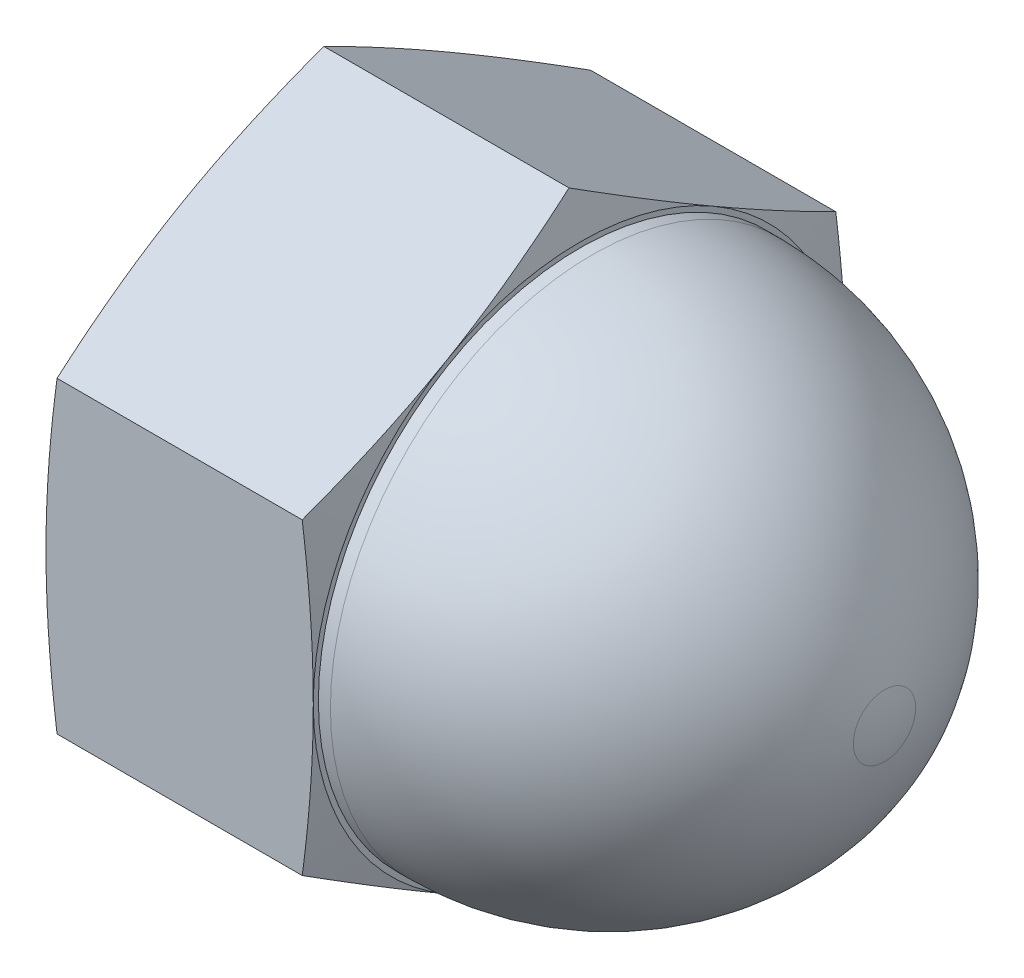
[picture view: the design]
ISO-10303-21;
HEADER;
FILE_DESCRIPTION(('STEP AP214'),'2;1');
FILE_NAME('part.step','',(''),(''),'','','');
FILE_SCHEMA(('AUTOMOTIVE_DESIGN { 1 0 10303 214 1 1 1 1 }'));
ENDSEC;
DATA;
#1=APPLICATION_CONTEXT('core data for automotive mechanical design processes');
#2=APPLICATION_PROTOCOL_DEFINITION('international standard','automotive_design',2000,#1);
#3=PRODUCT_CONTEXT('',#1,'mechanical');
#4=PRODUCT('Part','Part','',(#3));
#5=PRODUCT_RELATED_PRODUCT_CATEGORY('part','',(#4));
#6=PRODUCT_DEFINITION_FORMATION('','',#4);
#7=PRODUCT_DEFINITION_CONTEXT('part definition',#1,'design');
#8=PRODUCT_DEFINITION('design','',#6,#7);
#9=PRODUCT_DEFINITION_SHAPE('','',#8);
#10=(LENGTH_UNIT() NAMED_UNIT(*) SI_UNIT(.MILLI.,.METRE.));
#11=(NAMED_UNIT(*) PLANE_ANGLE_UNIT() SI_UNIT($,.RADIAN.));
#12=(NAMED_UNIT(*) SI_UNIT($,.STERADIAN.) SOLID_ANGLE_UNIT());
#13=UNCERTAINTY_MEASURE_WITH_UNIT(LENGTH_MEASURE(1.E-05),#10,'distance_accuracy_value','');
#14=(GEOMETRIC_REPRESENTATION_CONTEXT(3) GLOBAL_UNCERTAINTY_ASSIGNED_CONTEXT((#13)) GLOBAL_UNIT_ASSIGNED_CONTEXT((#10,
#11,#12)) REPRESENTATION_CONTEXT('',''));
#15=CARTESIAN_POINT('',(0.,0.,0.));
#16=DIRECTION('',(0.,0.,1.));
#17=DIRECTION('',(1.,0.,0.));
#18=AXIS2_PLACEMENT_3D('',#15,#16,#17);
#19=CARTESIAN_POINT('',(18.288,21.0805017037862,0.));
#20=DIRECTION('',(-1.,0.,0.));
#21=DIRECTION('',(0.,0.,1.));
#22=AXIS2_PLACEMENT_3D('',#19,#20,#21);
#23=PLANE('',#22);
#24=CARTESIAN_POINT('',(18.288,0.,0.));
#25=DIRECTION('',(-1.,0.,0.));
#26=DIRECTION('',(0.,0.,1.));
#27=AXIS2_PLACEMENT_3D('',#24,#25,#26);
#28=CIRCLE('',#27,17.907);
#29=CARTESIAN_POINT('',(18.288,0.,17.907));
#30=VERTEX_POINT('',#29);
#31=EDGE_CURVE('E308',#30,#30,#28,.F.);
#32=ORIENTED_EDGE('',*,*,#31,.F.);
#33=EDGE_LOOP('',(#32));
#34=FACE_BOUND('',#33,.T.);
#35=CARTESIAN_POINT('',(18.288,0.,0.));
#36=DIRECTION('',(-1.,0.,0.));
#37=DIRECTION('',(0.,0.,1.));
#38=AXIS2_PLACEMENT_3D('',#35,#36,#37);
#39=CIRCLE('',#38,18.25625);
#40=CARTESIAN_POINT('',(18.288,0.,18.25625));
#41=VERTEX_POINT('',#40);
#42=CARTESIAN_POINT('',(18.288,15.8103762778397,9.12812499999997));
#43=VERTEX_POINT('',#42);
#44=EDGE_CURVE('E279',#41,#43,#39,.T.);
#45=ORIENTED_EDGE('',*,*,#44,.F.);
#46=CARTESIAN_POINT('',(18.288,0.,0.));
#47=DIRECTION('',(-1.,0.,0.));
#48=DIRECTION('',(0.,0.,1.));
#49=AXIS2_PLACEMENT_3D('',#46,#47,#48);
#50=CIRCLE('',#49,18.25625);
#51=CARTESIAN_POINT('',(18.288,-15.8103762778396,9.12812500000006));
#52=VERTEX_POINT('',#51);
#53=EDGE_CURVE('E44',#52,#41,#50,.T.);
#54=ORIENTED_EDGE('',*,*,#53,.F.);
#55=CARTESIAN_POINT('',(18.288,-15.8103762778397,-9.12812499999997));
#56=VERTEX_POINT('',#55);
#57=EDGE_CURVE('E302',#56,#52,#50,.T.);
#58=ORIENTED_EDGE('',*,*,#57,.F.);
#59=CARTESIAN_POINT('',(18.288,0.,-18.25625));
#60=VERTEX_POINT('',#59);
#61=EDGE_CURVE('E360',#60,#56,#50,.T.);
#62=ORIENTED_EDGE('',*,*,#61,.F.);
#63=CARTESIAN_POINT('',(18.288,15.8103762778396,-9.12812500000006));
#64=VERTEX_POINT('',#63);
#65=EDGE_CURVE('E42',#64,#60,#50,.T.);
#66=ORIENTED_EDGE('',*,*,#65,.F.);
#67=EDGE_CURVE('E11',#43,#64,#50,.T.);
#68=ORIENTED_EDGE('',*,*,#67,.F.);
#69=EDGE_LOOP('',(#45,#54,#58,#62,#66,#68));
#70=FACE_BOUND('',#69,.T.);
#71=ADVANCED_FACE('F32',(#34,#70),#23,.F.);
#72=CARTESIAN_POINT('',(0.,0.,0.));
#73=DIRECTION('',(-1.,0.,0.));
#74=DIRECTION('',(0.,0.,1.));
#75=AXIS2_PLACEMENT_3D('',#72,#73,#74);
#76=CYLINDRICAL_SURFACE('',#75,17.907);
#77=CARTESIAN_POINT('',(19.1115044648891,0.,0.));
#78=DIRECTION('',(-1.,0.,0.));
#79=DIRECTION('',(0.,0.,1.));
#80=AXIS2_PLACEMENT_3D('',#77,#78,#79);
#81=CIRCLE('',#80,17.907);
#82=CARTESIAN_POINT('',(19.1115044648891,0.,17.907));
#83=VERTEX_POINT('',#82);
#84=EDGE_CURVE('E326',#83,#83,#81,.T.);
#85=ORIENTED_EDGE('',*,*,#84,.T.);
#86=EDGE_LOOP('',(#85));
#87=FACE_BOUND('',#86,.T.);
#88=ORIENTED_EDGE('',*,*,#31,.T.);
#89=EDGE_LOOP('',(#88));
#90=FACE_BOUND('',#89,.T.);
#91=ADVANCED_FACE('F145',(#87,#90),#76,.T.);
#92=CARTESIAN_POINT('',(19.1115044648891,0.,0.));
#93=DIRECTION('',(-1.,0.,0.));
#94=DIRECTION('',(0.,0.,1.));
#95=AXIS2_PLACEMENT_3D('',#92,#93,#94);
#96=DEGENERATE_TOROIDAL_SURFACE('',#95,2.66700000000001,20.574,.F.);
#97=ORIENTED_EDGE('',*,*,#84,.F.);
#98=EDGE_LOOP('',(#97));
#99=FACE_BOUND('',#98,.T.);
#100=CARTESIAN_POINT('',(39.1175964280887,0.,0.));
#101=DIRECTION('',(-1.,0.,0.));
#102=DIRECTION('',(0.,0.,1.));
#103=AXIS2_PLACEMENT_3D('',#100,#101,#102);
#104=CIRCLE('',#103,2.13360000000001);
#105=CARTESIAN_POINT('',(39.1175964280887,0.,2.13360000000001));
#106=VERTEX_POINT('',#105);
#107=EDGE_CURVE('E330',#106,#106,#104,.T.);
#108=ORIENTED_EDGE('',*,*,#107,.T.);
#109=EDGE_LOOP('',(#108));
#110=FACE_BOUND('',#109,.T.);
#111=ADVANCED_FACE('F151',(#99,#110),#96,.F.);
#112=CARTESIAN_POINT('',(30.226,0.,0.));
#113=DIRECTION('',(-1.,0.,0.));
#114=DIRECTION('',(0.,1.,0.));
#115=AXIS2_PLACEMENT_3D('',#112,#113,#114);
#116=SPHERICAL_SURFACE('',#115,9.144);
#117=ORIENTED_EDGE('',*,*,#107,.F.);
#118=EDGE_LOOP('',(#117));
#119=FACE_BOUND('',#118,.T.);
#120=ADVANCED_FACE('F210',(#119),#116,.T.);
#121=CARTESIAN_POINT('',(16.3329343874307,0.,0.));
#122=DIRECTION('',(-1.,0.,0.));
#123=DIRECTION('',(0.,0.,1.));
#124=AXIS2_PLACEMENT_3D('',#121,#122,#123);
#125=CONICAL_SURFACE('',#124,25.5539793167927,1.30904233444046);
#126=CARTESIAN_POINT('',(14.23452834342,-27.9532654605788,18.25625));
#127=CARTESIAN_POINT('',(14.3275034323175,-27.5387474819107,18.25625));
#128=CARTESIAN_POINT('',(14.4198935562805,-27.1240983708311,18.25625));
#129=CARTESIAN_POINT('',(14.6033753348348,-26.2945115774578,18.25625));
#130=CARTESIAN_POINT('',(14.6944669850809,-25.8795738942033,18.25625));
#131=CARTESIAN_POINT('',(14.9656076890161,-24.6342596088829,18.25625));
#132=CARTESIAN_POINT('',(15.1435150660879,-23.8034148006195,18.25625));
#133=CARTESIAN_POINT('',(15.4925052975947,-22.1394500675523,18.25625));
#134=CARTESIAN_POINT('',(15.6635813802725,-21.306328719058,18.25625));
#135=CARTESIAN_POINT('',(15.9970880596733,-19.6383578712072,18.25625));
#136=CARTESIAN_POINT('',(16.1595187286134,-18.8035083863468,18.25625));
#137=CARTESIAN_POINT('',(16.4724176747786,-17.1384385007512,18.25625));
#138=CARTESIAN_POINT('',(16.622970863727,-16.3082341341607,18.25625));
#139=CARTESIAN_POINT('',(16.9110143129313,-14.6455443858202,18.25625));
#140=CARTESIAN_POINT('',(17.0485045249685,-13.8130589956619,18.25625));
#141=CARTESIAN_POINT('',(17.3073349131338,-12.1456689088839,18.25625));
#142=CARTESIAN_POINT('',(17.428677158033,-11.3107645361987,18.25625));
#143=CARTESIAN_POINT('',(17.6516508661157,-9.63829765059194,18.25625));
#144=CARTESIAN_POINT('',(17.7532823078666,-8.80073513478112,18.25625));
#145=CARTESIAN_POINT('',(17.9339717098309,-7.11347642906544,18.25625));
#146=CARTESIAN_POINT('',(18.0127589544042,-6.26375081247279,18.25625));
#147=CARTESIAN_POINT('',(18.1423348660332,-4.56214896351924,18.25625));
#148=CARTESIAN_POINT('',(18.1931241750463,-3.71027278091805,18.25625));
#149=CARTESIAN_POINT('',(18.2637429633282,-2.00560726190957,18.25625));
#150=CARTESIAN_POINT('',(18.2835867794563,-1.15281853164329,18.25625));
#151=CARTESIAN_POINT('',(18.2910929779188,0.552902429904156,18.25625));
#152=CARTESIAN_POINT('',(18.278755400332,1.40583466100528,18.25625));
#153=CARTESIAN_POINT('',(18.2225918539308,3.11375554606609,18.25625));
#154=CARTESIAN_POINT('',(18.1786511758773,3.96874035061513,18.25625));
#155=CARTESIAN_POINT('',(18.0617958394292,5.67670937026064,18.25625));
#156=CARTESIAN_POINT('',(17.9888805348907,6.52969354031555,18.25625));
#157=CARTESIAN_POINT('',(17.8177764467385,8.23365261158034,18.25625));
#158=CARTESIAN_POINT('',(17.7195710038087,9.08462581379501,18.25625));
#159=CARTESIAN_POINT('',(17.5019945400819,10.7838317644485,18.25625));
#160=CARTESIAN_POINT('',(17.3826234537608,11.6320645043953,18.25625));
#161=CARTESIAN_POINT('',(17.134092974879,13.2760153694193,18.25625));
#162=CARTESIAN_POINT('',(17.0059238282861,14.0718847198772,18.25625));
#163=CARTESIAN_POINT('',(16.7370148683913,15.6615074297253,18.25625));
#164=CARTESIAN_POINT('',(16.5962747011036,16.4552607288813,18.25625));
#165=CARTESIAN_POINT('',(16.304536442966,18.0409557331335,18.25625));
#166=CARTESIAN_POINT('',(16.1535372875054,18.8328972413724,18.25625));
#167=CARTESIAN_POINT('',(15.8431874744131,20.415128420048,18.25625));
#168=CARTESIAN_POINT('',(15.6838368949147,21.2054181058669,18.25625));
#169=CARTESIAN_POINT('',(15.358261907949,22.7847826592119,18.25625));
#170=CARTESIAN_POINT('',(15.1920357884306,23.5738571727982,18.25625));
#171=CARTESIAN_POINT('',(14.85396082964,25.1507994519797,18.25625));
#172=CARTESIAN_POINT('',(14.6821119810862,25.9386672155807,18.25625));
#173=CARTESIAN_POINT('',(14.3337740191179,27.5133202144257,18.25625));
#174=CARTESIAN_POINT('',(14.1572852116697,28.3001055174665,18.25625));
#175=CARTESIAN_POINT('',(13.8004259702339,29.8727961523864,18.25625));
#176=CARTESIAN_POINT('',(13.6200555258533,30.6587014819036,18.25625));
#177=CARTESIAN_POINT('',(13.0776878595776,32.9997553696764,18.25625));
#178=CARTESIAN_POINT('',(12.7109621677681,34.5538083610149,18.25625));
#179=CARTESIAN_POINT('',(11.9683855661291,37.6597542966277,18.25625));
#180=CARTESIAN_POINT('',(11.5925344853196,39.2116471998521,18.25625));
#181=CARTESIAN_POINT('',(10.8345439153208,42.3118217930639,18.25625));
#182=CARTESIAN_POINT('',(10.4524129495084,43.8601055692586,18.25625));
#183=CARTESIAN_POINT('',(9.87538294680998,46.1815493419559,18.25625));
#184=CARTESIAN_POINT('',(9.68240387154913,46.9551876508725,18.25625));
#185=CARTESIAN_POINT('',(9.29531367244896,48.5021801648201,18.25625));
#186=CARTESIAN_POINT('',(9.10120254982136,49.2755343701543,18.25625));
#187=CARTESIAN_POINT('',(8.90659910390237,50.0487647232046,18.25625));
#188=B_SPLINE_CURVE_WITH_KNOTS('',3,(#126,#127,#128,#129,#130,#131,#132,#133,#134,#135,#136,
#137,#138,#139,#140,#141,#142,#143,#144,#145,#146,#147,#148,#149,#150,#151,#152,#153,#154,#155,
#156,#157,#158,#159,#160,#161,#162,#163,#164,#165,#166,#167,#168,#169,#170,#171,#172,#173,#174,
#175,#176,#177,#178,#179,#180,#181,#182,#183,#184,#185,#186,#187),.UNSPECIFIED.,.F.,.F.,(4,2,2,
2,2,2,2,2,2,2,2,2,2,2,2,2,2,2,2,2,2,2,2,2,2,2,2,2,2,2,4),(0.,1.27445034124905,2.54890494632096,
5.0979157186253,7.64939354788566,10.2008500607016,12.7320016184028,15.2631625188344,
17.7939988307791,20.3248378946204,22.8845458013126,25.4441950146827,28.0026580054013,
30.5611178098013,33.1289111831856,35.6967618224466,38.2663083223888,40.8358627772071,
43.2541145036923,45.6724343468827,48.0910055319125,50.509554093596,52.928708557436,
55.3478670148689,57.7668663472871,60.1858721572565,64.976038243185,69.7662941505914,
74.5505121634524,76.9425429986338,79.3345712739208),.UNSPECIFIED.);
#189=CARTESIAN_POINT('',(17.5313814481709,-10.5402508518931,18.25625));
#190=VERTEX_POINT('',#189);
#191=EDGE_CURVE('E233',#41,#190,#188,.F.);
#192=ORIENTED_EDGE('',*,*,#191,.T.);
#193=CARTESIAN_POINT('',(17.5313505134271,-10.5401353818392,18.25645));
#194=CARTESIAN_POINT('',(17.5899853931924,-10.7590105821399,17.8773470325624));
#195=CARTESIAN_POINT('',(17.6459340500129,-10.978065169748,17.4979333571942));
#196=CARTESIAN_POINT('',(17.7519028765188,-11.4165429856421,16.7384675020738));
#197=CARTESIAN_POINT('',(17.8019227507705,-11.6359662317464,16.3584152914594));
#198=CARTESIAN_POINT('',(17.9422800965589,-12.2949280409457,15.2170599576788));
#199=CARTESIAN_POINT('',(18.0228725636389,-12.7350021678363,14.4548292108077));
#200=CARTESIAN_POINT('',(18.1534715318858,-13.6140162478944,12.9323321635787));
#201=CARTESIAN_POINT('',(18.2036336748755,-14.0529503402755,12.1720760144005));
#202=CARTESIAN_POINT('',(18.2708947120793,-14.9313817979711,10.650588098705));
#203=CARTESIAN_POINT('',(18.288,-15.3708790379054,9.88935654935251));
#204=CARTESIAN_POINT('',(18.288,-16.249873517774,8.36689345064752));
#205=CARTESIAN_POINT('',(18.2708947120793,-16.6893707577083,7.60566190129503));
#206=CARTESIAN_POINT('',(18.2036336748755,-17.5678022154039,6.08417398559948));
#207=CARTESIAN_POINT('',(18.1534715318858,-18.0067363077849,5.32391783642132));
#208=CARTESIAN_POINT('',(18.0228725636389,-18.885750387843,3.80142078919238));
#209=CARTESIAN_POINT('',(17.9422800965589,-19.3258245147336,3.03919004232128));
#210=CARTESIAN_POINT('',(17.8019227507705,-19.9847863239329,1.89783470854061));
#211=CARTESIAN_POINT('',(17.7519028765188,-20.2042095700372,1.51778249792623));
#212=CARTESIAN_POINT('',(17.6459340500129,-20.6426873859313,0.758316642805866));
#213=CARTESIAN_POINT('',(17.5899853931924,-20.8617419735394,0.378902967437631));
#214=CARTESIAN_POINT('',(17.5313505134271,-21.0806171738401,-0.000199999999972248));
#215=B_SPLINE_CURVE_WITH_KNOTS('',3,(#193,#194,#195,#196,#197,#198,#199,#200,#201,#202,#203,
#204,#205,#206,#207,#208,#209,#210,#211,#212,#213,#214),.UNSPECIFIED.,.F.,.F.,(4,2,2,2,2,2,2,2,
2,2,4),(0.,1.32496515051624,2.64999629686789,5.30100599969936,7.93833969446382,10.5751632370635,
13.2119867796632,15.8493204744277,18.5003301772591,19.8253613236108,21.150326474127),.UNSPECIFIED.);
#216=EDGE_CURVE('E231',#190,#52,#215,.T.);
#217=ORIENTED_EDGE('',*,*,#216,.T.);
#218=ORIENTED_EDGE('',*,*,#53,.T.);
#219=EDGE_LOOP('',(#192,#217,#218));
#220=FACE_BOUND('',#219,.T.);
#221=ADVANCED_FACE('F356',(#220),#125,.T.);
#222=CARTESIAN_POINT('',(17.5313814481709,-21.0805017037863,0.));
#223=VERTEX_POINT('',#222);
#224=EDGE_CURVE('E226',#52,#223,#215,.T.);
#225=ORIENTED_EDGE('',*,*,#224,.T.);
#226=CARTESIAN_POINT('',(17.5313505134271,-21.0806171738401,0.000200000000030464));
#227=CARTESIAN_POINT('',(17.5899853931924,-20.8617419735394,-0.378902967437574));
#228=CARTESIAN_POINT('',(17.6459340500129,-20.6426873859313,-0.758316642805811));
#229=CARTESIAN_POINT('',(17.7519028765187,-20.2042095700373,-1.51778249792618));
#230=CARTESIAN_POINT('',(17.8019227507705,-19.9847863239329,-1.89783470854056));
#231=CARTESIAN_POINT('',(17.9422800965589,-19.3258245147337,-3.03919004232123));
#232=CARTESIAN_POINT('',(18.0228725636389,-18.885750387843,-3.80142078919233));
#233=CARTESIAN_POINT('',(18.1534715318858,-18.006736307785,-5.32391783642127));
#234=CARTESIAN_POINT('',(18.2036336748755,-17.5678022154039,-6.08417398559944));
#235=CARTESIAN_POINT('',(18.2708947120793,-16.6893707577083,-7.60566190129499));
#236=CARTESIAN_POINT('',(18.288,-16.249873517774,-8.36689345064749));
#237=CARTESIAN_POINT('',(18.288,-15.3708790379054,-9.88935654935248));
#238=CARTESIAN_POINT('',(18.2708947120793,-14.9313817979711,-10.650588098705));
#239=CARTESIAN_POINT('',(18.2036336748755,-14.0529503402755,-12.1720760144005));
#240=CARTESIAN_POINT('',(18.1534715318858,-13.6140162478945,-12.9323321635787));
#241=CARTESIAN_POINT('',(18.0228725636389,-12.7350021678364,-14.4548292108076));
#242=CARTESIAN_POINT('',(17.9422800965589,-12.2949280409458,-15.2170599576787));
#243=CARTESIAN_POINT('',(17.8019227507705,-11.6359662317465,-16.3584152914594));
#244=CARTESIAN_POINT('',(17.7519028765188,-11.4165429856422,-16.7384675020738));
#245=CARTESIAN_POINT('',(17.6459340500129,-10.9780651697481,-17.4979333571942));
#246=CARTESIAN_POINT('',(17.5899853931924,-10.75901058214,-17.8773470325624));
#247=CARTESIAN_POINT('',(17.5313505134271,-10.5401353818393,-18.25645));
#248=B_SPLINE_CURVE_WITH_KNOTS('',3,(#226,#227,#228,#229,#230,#231,#232,#233,#234,#235,#236,
#237,#238,#239,#240,#241,#242,#243,#244,#245,#246,#247),.UNSPECIFIED.,.F.,.F.,(4,2,2,2,2,2,2,2,
2,2,4),(0.,1.32496515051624,2.64999629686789,5.30100599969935,7.93833969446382,10.5751632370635,
13.2119867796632,15.8493204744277,18.5003301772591,19.8253613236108,21.150326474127),.UNSPECIFIED.);
#249=EDGE_CURVE('E232',#223,#56,#248,.T.);
#250=ORIENTED_EDGE('',*,*,#249,.T.);
#251=ORIENTED_EDGE('',*,*,#57,.T.);
#252=EDGE_LOOP('',(#225,#250,#251));
#253=FACE_BOUND('',#252,.T.);
#254=ADVANCED_FACE('F362',(#253),#125,.T.);
#255=CARTESIAN_POINT('',(17.5313814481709,-10.5402508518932,-18.25625));
#256=VERTEX_POINT('',#255);
#257=EDGE_CURVE('E221',#56,#256,#248,.T.);
#258=ORIENTED_EDGE('',*,*,#257,.T.);
#259=CARTESIAN_POINT('',(14.23452834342,-27.953265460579,-18.25625));
#260=CARTESIAN_POINT('',(14.3275034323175,-27.5387474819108,-18.25625));
#261=CARTESIAN_POINT('',(14.4198935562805,-27.1240983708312,-18.25625));
#262=CARTESIAN_POINT('',(14.6033753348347,-26.2945115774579,-18.25625));
#263=CARTESIAN_POINT('',(14.6944669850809,-25.8795738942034,-18.25625));
#264=CARTESIAN_POINT('',(14.965607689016,-24.634259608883,-18.25625));
#265=CARTESIAN_POINT('',(15.1435150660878,-23.8034148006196,-18.25625));
#266=CARTESIAN_POINT('',(15.4925052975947,-22.1394500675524,-18.25625));
#267=CARTESIAN_POINT('',(15.6635813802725,-21.3063287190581,-18.25625));
#268=CARTESIAN_POINT('',(15.9970880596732,-19.6383578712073,-18.25625));
#269=CARTESIAN_POINT('',(16.1595187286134,-18.8035083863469,-18.25625));
#270=CARTESIAN_POINT('',(16.4724176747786,-17.1384385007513,-18.25625));
#271=CARTESIAN_POINT('',(16.622970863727,-16.3082341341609,-18.25625));
#272=CARTESIAN_POINT('',(16.9110143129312,-14.6455443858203,-18.25625));
#273=CARTESIAN_POINT('',(17.0485045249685,-13.813058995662,-18.25625));
#274=CARTESIAN_POINT('',(17.3073349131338,-12.145668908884,-18.25625));
#275=CARTESIAN_POINT('',(17.428677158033,-11.3107645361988,-18.25625));
#276=CARTESIAN_POINT('',(17.6516508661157,-9.63829765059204,-18.25625));
#277=CARTESIAN_POINT('',(17.7532823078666,-8.80073513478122,-18.25625));
#278=CARTESIAN_POINT('',(17.9339717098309,-7.11347642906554,-18.25625));
#279=CARTESIAN_POINT('',(18.0127589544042,-6.26375081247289,-18.25625));
#280=CARTESIAN_POINT('',(18.1423348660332,-4.56214896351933,-18.25625));
#281=CARTESIAN_POINT('',(18.1931241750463,-3.71027278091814,-18.25625));
#282=CARTESIAN_POINT('',(18.2637429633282,-2.00560726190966,-18.25625));
#283=CARTESIAN_POINT('',(18.2835867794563,-1.15281853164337,-18.25625));
#284=CARTESIAN_POINT('',(18.2910929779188,0.55290242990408,-18.25625));
#285=CARTESIAN_POINT('',(18.278755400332,1.40583466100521,-18.25625));
#286=CARTESIAN_POINT('',(18.2225918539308,3.11375554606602,-18.25625));
#287=CARTESIAN_POINT('',(18.1786511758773,3.96874035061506,-18.25625));
#288=CARTESIAN_POINT('',(18.0617958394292,5.67670937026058,-18.25625));
#289=CARTESIAN_POINT('',(17.9888805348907,6.52969354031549,-18.25625));
#290=CARTESIAN_POINT('',(17.8177764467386,8.23365261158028,-18.25625));
#291=CARTESIAN_POINT('',(17.7195710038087,9.08462581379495,-18.25625));
#292=CARTESIAN_POINT('',(17.5019945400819,10.7838317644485,-18.25625));
#293=CARTESIAN_POINT('',(17.3826234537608,11.6320645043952,-18.25625));
#294=CARTESIAN_POINT('',(17.134092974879,13.2760153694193,-18.25625));
#295=CARTESIAN_POINT('',(17.0059238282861,14.0718847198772,-18.25625));
#296=CARTESIAN_POINT('',(16.7370148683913,15.6615074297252,-18.25625));
#297=CARTESIAN_POINT('',(16.5962747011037,16.4552607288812,-18.25625));
#298=CARTESIAN_POINT('',(16.304536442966,18.0409557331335,-18.25625));
#299=CARTESIAN_POINT('',(16.1535372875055,18.8328972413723,-18.25625));
#300=CARTESIAN_POINT('',(15.8431874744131,20.415128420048,-18.25625));
#301=CARTESIAN_POINT('',(15.6838368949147,21.2054181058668,-18.25625));
#302=CARTESIAN_POINT('',(15.358261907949,22.7847826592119,-18.25625));
#303=CARTESIAN_POINT('',(15.1920357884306,23.5738571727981,-18.25625));
#304=CARTESIAN_POINT('',(14.85396082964,25.1507994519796,-18.25625));
#305=CARTESIAN_POINT('',(14.6821119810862,25.9386672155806,-18.25625));
#306=CARTESIAN_POINT('',(14.3337740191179,27.5133202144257,-18.25625));
#307=CARTESIAN_POINT('',(14.1572852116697,28.3001055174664,-18.25625));
#308=CARTESIAN_POINT('',(13.8004259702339,29.8727961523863,-18.25625));
#309=CARTESIAN_POINT('',(13.6200555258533,30.6587014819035,-18.25625));
#310=CARTESIAN_POINT('',(13.0776878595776,32.9997553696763,-18.25625));
#311=CARTESIAN_POINT('',(12.7109621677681,34.5538083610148,-18.25625));
#312=CARTESIAN_POINT('',(11.9683855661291,37.6597542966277,-18.25625));
#313=CARTESIAN_POINT('',(11.5925344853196,39.2116471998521,-18.25625));
#314=CARTESIAN_POINT('',(10.8345439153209,42.3118217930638,-18.25625));
#315=CARTESIAN_POINT('',(10.4524129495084,43.8601055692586,-18.25625));
#316=CARTESIAN_POINT('',(9.87538294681,46.1815493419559,-18.25625));
#317=CARTESIAN_POINT('',(9.68240387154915,46.9551876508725,-18.25625));
#318=CARTESIAN_POINT('',(9.29531367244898,48.5021801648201,-18.25625));
#319=CARTESIAN_POINT('',(9.10120254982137,49.2755343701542,-18.25625));
#320=CARTESIAN_POINT('',(8.90659910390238,50.0487647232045,-18.25625));
#321=B_SPLINE_CURVE_WITH_KNOTS('',3,(#259,#260,#261,#262,#263,#264,#265,#266,#267,#268,#269,
#270,#271,#272,#273,#274,#275,#276,#277,#278,#279,#280,#281,#282,#283,#284,#285,#286,#287,#288,
#289,#290,#291,#292,#293,#294,#295,#296,#297,#298,#299,#300,#301,#302,#303,#304,#305,#306,#307,
#308,#309,#310,#311,#312,#313,#314,#315,#316,#317,#318,#319,#320),.UNSPECIFIED.,.F.,.F.,(4,2,2,
2,2,2,2,2,2,2,2,2,2,2,2,2,2,2,2,2,2,2,2,2,2,2,2,2,2,2,4),(0.,1.27445034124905,2.54890494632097,
5.09791571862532,7.64939354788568,10.2008500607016,12.7320016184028,15.2631625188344,
17.7939988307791,20.3248378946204,22.8845458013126,25.4441950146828,28.0026580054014,
30.5611178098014,33.1289111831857,35.6967618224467,38.2663083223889,40.8358627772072,
43.2541145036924,45.6724343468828,48.0910055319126,50.5095540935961,52.9287085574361,
55.347867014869,57.7668663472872,60.1858721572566,64.9760382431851,69.7662941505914,
74.5505121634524,76.9425429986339,79.3345712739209),.UNSPECIFIED.);
#322=EDGE_CURVE('E58',#60,#256,#321,.F.);
#323=ORIENTED_EDGE('',*,*,#322,.F.);
#324=ORIENTED_EDGE('',*,*,#61,.T.);
#325=EDGE_LOOP('',(#258,#323,#324));
#326=FACE_BOUND('',#325,.T.);
#327=ADVANCED_FACE('F206',(#326),#125,.T.);
#328=CARTESIAN_POINT('',(17.5313505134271,10.5401353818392,-18.25645));
#329=CARTESIAN_POINT('',(17.5899853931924,10.7590105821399,-17.8773470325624));
#330=CARTESIAN_POINT('',(17.6459340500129,10.978065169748,-17.4979333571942));
#331=CARTESIAN_POINT('',(17.7519028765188,11.4165429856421,-16.7384675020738));
#332=CARTESIAN_POINT('',(17.8019227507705,11.6359662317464,-16.3584152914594));
#333=CARTESIAN_POINT('',(17.9422800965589,12.2949280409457,-15.2170599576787));
#334=CARTESIAN_POINT('',(18.0228725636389,12.7350021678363,-14.4548292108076));
#335=CARTESIAN_POINT('',(18.1534715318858,13.6140162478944,-12.9323321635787));
#336=CARTESIAN_POINT('',(18.2036336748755,14.0529503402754,-12.1720760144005));
#337=CARTESIAN_POINT('',(18.2708947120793,14.931381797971,-10.650588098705));
#338=CARTESIAN_POINT('',(18.288,15.3708790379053,-9.88935654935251));
#339=CARTESIAN_POINT('',(18.288,16.2498735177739,-8.36689345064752));
#340=CARTESIAN_POINT('',(18.2708947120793,16.6893707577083,-7.60566190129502));
#341=CARTESIAN_POINT('',(18.2036336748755,17.5678022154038,-6.08417398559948));
#342=CARTESIAN_POINT('',(18.1534715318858,18.0067363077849,-5.32391783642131));
#343=CARTESIAN_POINT('',(18.0228725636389,18.885750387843,-3.80142078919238));
#344=CARTESIAN_POINT('',(17.9422800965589,19.3258245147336,-3.03919004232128));
#345=CARTESIAN_POINT('',(17.8019227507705,19.9847863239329,-1.89783470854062));
#346=CARTESIAN_POINT('',(17.7519028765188,20.2042095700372,-1.51778249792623));
#347=CARTESIAN_POINT('',(17.6459340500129,20.6426873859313,-0.758316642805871));
#348=CARTESIAN_POINT('',(17.5899853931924,20.8617419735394,-0.378902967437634));
#349=CARTESIAN_POINT('',(17.5313505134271,21.0806171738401,0.000199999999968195));
#350=B_SPLINE_CURVE_WITH_KNOTS('',3,(#328,#329,#330,#331,#332,#333,#334,#335,#336,#337,#338,
#339,#340,#341,#342,#343,#344,#345,#346,#347,#348,#349),.UNSPECIFIED.,.F.,.F.,(4,2,2,2,2,2,2,2,
2,2,4),(0.,1.32496515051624,2.6499962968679,5.30100599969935,7.93833969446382,10.5751632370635,
13.2119867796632,15.8493204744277,18.5003301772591,19.8253613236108,21.150326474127),.UNSPECIFIED.);
#351=CARTESIAN_POINT('',(17.5313814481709,10.5402508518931,-18.25625));
#352=VERTEX_POINT('',#351);
#353=EDGE_CURVE('E189',#352,#64,#350,.T.);
#354=ORIENTED_EDGE('',*,*,#353,.T.);
#355=ORIENTED_EDGE('',*,*,#65,.T.);
#356=EDGE_CURVE('E196',#352,#60,#321,.F.);
#357=ORIENTED_EDGE('',*,*,#356,.F.);
#358=EDGE_LOOP('',(#354,#355,#357));
#359=FACE_BOUND('',#358,.T.);
#360=ADVANCED_FACE('F201',(#359),#125,.T.);
#361=CARTESIAN_POINT('',(17.5313505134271,21.0806171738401,-0.000200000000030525));
#362=CARTESIAN_POINT('',(17.5899853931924,20.8617419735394,0.378902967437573));
#363=CARTESIAN_POINT('',(17.6459340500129,20.6426873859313,0.75831664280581));
#364=CARTESIAN_POINT('',(17.7519028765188,20.2042095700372,1.51778249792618));
#365=CARTESIAN_POINT('',(17.8019227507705,19.9847863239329,1.89783470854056));
#366=CARTESIAN_POINT('',(17.9422800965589,19.3258245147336,3.03919004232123));
#367=CARTESIAN_POINT('',(18.0228725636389,18.885750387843,3.80142078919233));
#368=CARTESIAN_POINT('',(18.1534715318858,18.006736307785,5.32391783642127));
#369=CARTESIAN_POINT('',(18.2036336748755,17.5678022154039,6.08417398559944));
#370=CARTESIAN_POINT('',(18.2708947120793,16.6893707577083,7.60566190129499));
#371=CARTESIAN_POINT('',(18.288,16.249873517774,8.36689345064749));
#372=CARTESIAN_POINT('',(18.288,15.3708790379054,9.88935654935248));
#373=CARTESIAN_POINT('',(18.2708947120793,14.9313817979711,10.650588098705));
#374=CARTESIAN_POINT('',(18.2036336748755,14.0529503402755,12.1720760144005));
#375=CARTESIAN_POINT('',(18.1534715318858,13.6140162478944,12.9323321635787));
#376=CARTESIAN_POINT('',(18.0228725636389,12.7350021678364,14.4548292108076));
#377=CARTESIAN_POINT('',(17.9422800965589,12.2949280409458,15.2170599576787));
#378=CARTESIAN_POINT('',(17.8019227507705,11.6359662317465,16.3584152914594));
#379=CARTESIAN_POINT('',(17.7519028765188,11.4165429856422,16.7384675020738));
#380=CARTESIAN_POINT('',(17.6459340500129,10.9780651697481,17.4979333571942));
#381=CARTESIAN_POINT('',(17.5899853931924,10.75901058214,17.8773470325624));
#382=CARTESIAN_POINT('',(17.5313505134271,10.5401353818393,18.25645));
#383=B_SPLINE_CURVE_WITH_KNOTS('',3,(#361,#362,#363,#364,#365,#366,#367,#368,#369,#370,#371,
#372,#373,#374,#375,#376,#377,#378,#379,#380,#381,#382),.UNSPECIFIED.,.F.,.F.,(4,2,2,2,2,2,2,2,
2,2,4),(0.,1.32496515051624,2.6499962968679,5.30100599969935,7.93833969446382,10.5751632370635,
13.2119867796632,15.8493204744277,18.5003301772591,19.8253613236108,21.150326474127),.UNSPECIFIED.);
#384=CARTESIAN_POINT('',(17.5313814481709,21.0805017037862,0.));
#385=VERTEX_POINT('',#384);
#386=EDGE_CURVE('E50',#385,#43,#383,.T.);
#387=ORIENTED_EDGE('',*,*,#386,.T.);
#388=ORIENTED_EDGE('',*,*,#67,.T.);
#389=EDGE_CURVE('E182',#64,#385,#350,.T.);
#390=ORIENTED_EDGE('',*,*,#389,.T.);
#391=EDGE_LOOP('',(#387,#388,#390));
#392=FACE_BOUND('',#391,.T.);
#393=ADVANCED_FACE('F205',(#392),#125,.T.);
#394=CARTESIAN_POINT('',(17.5313814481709,10.5402508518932,18.25625));
#395=VERTEX_POINT('',#394);
#396=EDGE_CURVE('E332',#43,#395,#383,.T.);
#397=ORIENTED_EDGE('',*,*,#396,.T.);
#398=EDGE_CURVE('E335',#395,#41,#188,.F.);
#399=ORIENTED_EDGE('',*,*,#398,.T.);
#400=ORIENTED_EDGE('',*,*,#44,.T.);
#401=EDGE_LOOP('',(#397,#399,#400));
#402=FACE_BOUND('',#401,.T.);
#403=ADVANCED_FACE('F168',(#402),#125,.T.);
#404=CARTESIAN_POINT('',(18.288,10.5402508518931,-18.25625));
#405=DIRECTION('',(0.,-0.866025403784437,0.500000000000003));
#406=DIRECTION('',(0.,-0.500000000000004,-0.866025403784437));
#407=AXIS2_PLACEMENT_3D('',#404,#405,#406);
#408=PLANE('',#407);
#409=ORIENTED_EDGE('',*,*,#353,.F.);
#410=DIRECTION('',(-1.,0.,0.));
#411=VECTOR('',#410,1.);
#412=CARTESIAN_POINT('',(18.288,10.5402508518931,-18.25625));
#413=LINE('',#412,#411);
#414=CARTESIAN_POINT('',(0.75675596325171,10.5402508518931,-18.25625));
#415=VERTEX_POINT('',#414);
#416=EDGE_CURVE('E321',#352,#415,#413,.T.);
#417=ORIENTED_EDGE('',*,*,#416,.T.);
#418=CARTESIAN_POINT('',(0.756786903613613,21.0806171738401,0.000199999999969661));
#419=CARTESIAN_POINT('',(0.698141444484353,20.8617422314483,-0.378902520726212));
#420=CARTESIAN_POINT('',(0.64218267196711,20.6426878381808,-0.758315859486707));
#421=CARTESIAN_POINT('',(0.536194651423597,20.204210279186,-1.51778126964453));
#422=CARTESIAN_POINT('',(0.48616569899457,19.9847870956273,-1.8978333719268));
#423=CARTESIAN_POINT('',(0.345782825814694,19.3258252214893,-3.03918881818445));
#424=CARTESIAN_POINT('',(0.265175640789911,18.8857507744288,-3.80142011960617));
#425=CARTESIAN_POINT('',(0.134552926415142,18.0067364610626,-5.32391757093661));
#426=CARTESIAN_POINT('',(0.084381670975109,17.5678024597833,-6.08417356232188));
#427=CARTESIAN_POINT('',(0.0171084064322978,16.6893709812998,-7.60566151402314));
#428=CARTESIAN_POINT('',(0.,16.2498736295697,-8.36689325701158));
#429=CARTESIAN_POINT('',(0.,15.3708789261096,-9.88935674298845));
#430=CARTESIAN_POINT('',(0.0171084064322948,14.9313815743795,-10.6505884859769));
#431=CARTESIAN_POINT('',(0.0843816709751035,14.052950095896,-12.1720764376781));
#432=CARTESIAN_POINT('',(0.134552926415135,13.6140160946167,-12.9323324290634));
#433=CARTESIAN_POINT('',(0.265175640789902,12.7350017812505,-14.4548298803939));
#434=CARTESIAN_POINT('',(0.345782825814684,12.2949273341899,-15.2170611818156));
#435=CARTESIAN_POINT('',(0.486165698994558,11.635965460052,-16.3584166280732));
#436=CARTESIAN_POINT('',(0.536194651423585,11.4165422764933,-16.7384687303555));
#437=CARTESIAN_POINT('',(0.642182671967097,10.9780647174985,-17.4979341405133));
#438=CARTESIAN_POINT('',(0.698141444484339,10.7590103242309,-17.8773474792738));
#439=CARTESIAN_POINT('',(0.756786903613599,10.5401353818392,-18.25645));
#440=B_SPLINE_CURVE_WITH_KNOTS('',3,(#418,#419,#420,#421,#422,#423,#424,#425,#426,#427,#428,
#429,#430,#431,#432,#433,#434,#435,#436,#437,#438,#439),.UNSPECIFIED.,.F.,.F.,(4,2,2,2,2,2,2,2,
2,2,4),(0.,1.32496782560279,2.6500016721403,5.30101714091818,7.93835164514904,10.5751758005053,
13.2119999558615,15.8493344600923,18.5003499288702,19.8253837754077,21.1503516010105),.UNSPECIFIED.);
#441=CARTESIAN_POINT('',(0.,15.8103762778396,-9.12812500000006));
#442=VERTEX_POINT('',#441);
#443=EDGE_CURVE('E174',#442,#415,#440,.T.);
#444=ORIENTED_EDGE('',*,*,#443,.F.);
#445=CARTESIAN_POINT('',(0.756755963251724,21.0805017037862,0.));
#446=VERTEX_POINT('',#445);
#447=EDGE_CURVE('E269',#446,#442,#440,.T.);
#448=ORIENTED_EDGE('',*,*,#447,.F.);
#449=DIRECTION('',(-1.,0.,0.));
#450=VECTOR('',#449,1.);
#451=CARTESIAN_POINT('',(18.288,21.0805017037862,0.));
#452=LINE('',#451,#450);
#453=EDGE_CURVE('E323',#385,#446,#452,.T.);
#454=ORIENTED_EDGE('',*,*,#453,.F.);
#455=ORIENTED_EDGE('',*,*,#389,.F.);
#456=EDGE_LOOP('',(#409,#417,#444,#448,#454,#455));
#457=FACE_BOUND('',#456,.T.);
#458=ADVANCED_FACE('F163',(#457),#408,.F.);
#459=CARTESIAN_POINT('',(18.288,10.5402508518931,-18.25625));
#460=DIRECTION('',(0.,0.,-1.));
#461=DIRECTION('',(-1.,0.,0.));
#462=AXIS2_PLACEMENT_3D('',#459,#460,#461);
#463=PLANE('',#462);
#464=ORIENTED_EDGE('',*,*,#416,.F.);
#465=ORIENTED_EDGE('',*,*,#356,.T.);
#466=ORIENTED_EDGE('',*,*,#322,.T.);
#467=DIRECTION('',(-1.,0.,0.));
#468=VECTOR('',#467,1.);
#469=CARTESIAN_POINT('',(18.288,-10.5402508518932,-18.25625));
#470=LINE('',#469,#468);
#471=CARTESIAN_POINT('',(0.756755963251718,-10.5402508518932,-18.25625));
#472=VERTEX_POINT('',#471);
#473=EDGE_CURVE('E318',#256,#472,#470,.T.);
#474=ORIENTED_EDGE('',*,*,#473,.T.);
#475=CARTESIAN_POINT('',(4.05421920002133,-27.9533161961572,-18.25625));
#476=CARTESIAN_POINT('',(3.96122717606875,-27.5387982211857,-18.25625));
#477=CARTESIAN_POINT('',(3.86882021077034,-27.1241490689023,-18.25625));
#478=CARTESIAN_POINT('',(3.68530495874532,-26.29456209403,-18.25625));
#479=CARTESIAN_POINT('',(3.59419667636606,-25.8796242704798,-18.25625));
#480=CARTESIAN_POINT('',(3.32300641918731,-24.6343093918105,-18.25625));
#481=CARTESIAN_POINT('',(3.14506646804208,-23.8034639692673,-18.25625));
#482=CARTESIAN_POINT('',(2.79601214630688,-22.1394972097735,-18.25625));
#483=CARTESIAN_POINT('',(2.62490455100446,-21.3063744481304,-18.25625));
#484=CARTESIAN_POINT('',(2.29133629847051,-19.6384001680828,-18.25625));
#485=CARTESIAN_POINT('',(2.12887556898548,-18.8035486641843,-18.25625));
#486=CARTESIAN_POINT('',(1.81591904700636,-17.1384765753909,-18.25625));
#487=CARTESIAN_POINT('',(1.6653382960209,-16.3082720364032,-18.25625));
#488=CARTESIAN_POINT('',(1.37724193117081,-14.6455811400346,-18.25625));
#489=CARTESIAN_POINT('',(1.23972636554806,-13.8130947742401,-18.25625));
#490=CARTESIAN_POINT('',(0.980848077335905,-12.1457018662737,-18.25625));
#491=CARTESIAN_POINT('',(0.859483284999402,-11.3107956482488,-18.25625));
#492=CARTESIAN_POINT('',(0.636468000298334,-9.63832410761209,-18.25625));
#493=CARTESIAN_POINT('',(0.534817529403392,-8.8007587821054,-18.25625));
#494=CARTESIAN_POINT('',(0.354093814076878,-7.11348971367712,-18.25625));
#495=CARTESIAN_POINT('',(0.275291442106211,-6.26375652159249,-18.25625));
#496=CARTESIAN_POINT('',(0.145690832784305,-4.56213870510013,-18.25625));
#497=CARTESIAN_POINT('',(0.0948919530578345,-3.71025413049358,-18.25625));
#498=CARTESIAN_POINT('',(0.024260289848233,-2.00557150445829,-18.25625));
#499=CARTESIAN_POINT('',(0.00441316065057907,-1.15277405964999,-18.25625));
#500=CARTESIAN_POINT('',(-0.00309314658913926,0.552964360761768,-18.25625));
#501=CARTESIAN_POINT('',(0.00924763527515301,1.40590533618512,-18.25625));
#502=CARTESIAN_POINT('',(0.0654239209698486,3.11384444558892,-18.25625));
#503=CARTESIAN_POINT('',(0.109374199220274,3.96883872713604,-18.25625));
#504=CARTESIAN_POINT('',(0.226254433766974,5.67682590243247,-18.25625));
#505=CARTESIAN_POINT('',(0.299185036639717,6.52981875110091,-18.25625));
#506=CARTESIAN_POINT('',(0.470324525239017,8.23379443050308,-18.25625));
#507=CARTESIAN_POINT('',(0.56855008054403,9.08477556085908,-18.25625));
#508=CARTESIAN_POINT('',(0.786170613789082,10.7839963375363,-18.25625));
#509=CARTESIAN_POINT('',(0.905565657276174,11.6322359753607,-18.25625));
#510=CARTESIAN_POINT('',(1.15414497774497,13.2761953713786,-18.25625));
#511=CARTESIAN_POINT('',(1.28233876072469,14.0720664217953,-18.25625));
#512=CARTESIAN_POINT('',(1.55129899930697,15.6616917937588,-18.25625));
#513=CARTESIAN_POINT('',(1.69206580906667,16.4554460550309,-18.25625));
#514=CARTESIAN_POINT('',(1.98385895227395,18.0411423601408,-18.25625));
#515=CARTESIAN_POINT('',(2.13488635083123,18.833084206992,-18.25625));
#516=CARTESIAN_POINT('',(2.44529392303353,20.4153155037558,-18.25625));
#517=CARTESIAN_POINT('',(2.60467401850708,21.2056049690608,-18.25625));
#518=CARTESIAN_POINT('',(2.93030907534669,22.7849686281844,-18.25625));
#519=CARTESIAN_POINT('',(3.09656574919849,23.5740424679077,-18.25625));
#520=CARTESIAN_POINT('',(3.43470265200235,25.1509829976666,-18.25625));
#521=CARTESIAN_POINT('',(3.60658289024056,25.9388496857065,-18.25625));
#522=CARTESIAN_POINT('',(3.95498431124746,27.5135001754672,-18.25625));
#523=CARTESIAN_POINT('',(4.13150518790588,28.300284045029,-18.25625));
#524=CARTESIAN_POINT('',(4.48842913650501,29.87297152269,-18.25625));
#525=CARTESIAN_POINT('',(4.6688322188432,30.6588751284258,-18.25625));
#526=CARTESIAN_POINT('',(5.21129653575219,32.9999178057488,-18.25625));
#527=CARTESIAN_POINT('',(5.57808688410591,34.5539609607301,-18.25625));
#528=CARTESIAN_POINT('',(6.32079407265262,37.6598865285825,-18.25625));
#529=CARTESIAN_POINT('',(6.69671108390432,39.2117689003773,-18.25625));
#530=CARTESIAN_POINT('',(7.45483425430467,42.3119213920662,-18.25625));
#531=CARTESIAN_POINT('',(7.83703188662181,43.8601935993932,-18.25625));
#532=CARTESIAN_POINT('',(8.41416242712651,46.1816197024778,-18.25625));
#533=CARTESIAN_POINT('',(8.60717510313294,46.9552520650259,-18.25625));
#534=CARTESIAN_POINT('',(8.99433266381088,48.5022325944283,-18.25625));
#535=CARTESIAN_POINT('',(9.18847754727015,49.2755807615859,-18.25625));
#536=CARTESIAN_POINT('',(9.38311482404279,50.0488050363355,-18.25625));
#537=B_SPLINE_CURVE_WITH_KNOTS('',3,(#475,#476,#477,#478,#479,#480,#481,#482,#483,#484,#485,
#486,#487,#488,#489,#490,#491,#492,#493,#494,#495,#496,#497,#498,#499,#500,#501,#502,#503,#504,
#505,#506,#507,#508,#509,#510,#511,#512,#513,#514,#515,#516,#517,#518,#519,#520,#521,#522,#523,
#524,#525,#526,#527,#528,#529,#530,#531,#532,#533,#534,#535,#536),.UNSPECIFIED.,.F.,.F.,(4,2,2,
2,2,2,2,2,2,2,2,2,2,2,2,2,2,2,2,2,2,2,2,2,2,2,2,2,2,2,4),(0.,1.27446145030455,2.54892716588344,
5.09796019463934,7.64946118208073,10.2009408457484,12.7321076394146,15.2632837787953,
17.7941352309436,20.3249894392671,22.8847240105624,25.4443998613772,28.0028889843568,
30.5613749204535,33.1291979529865,35.6970782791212,38.2666552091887,40.8362400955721,
43.2545085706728,45.67284518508,48.0914332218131,50.5099986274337,52.9291700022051,
55.3483453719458,57.7673615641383,60.1863842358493,64.9765661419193,69.7668378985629,
74.5510701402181,76.9431080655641,79.335143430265),.UNSPECIFIED.);
#538=CARTESIAN_POINT('',(0.,0.,-18.25625));
#539=VERTEX_POINT('',#538);
#540=EDGE_CURVE('E263',#472,#539,#537,.T.);
#541=ORIENTED_EDGE('',*,*,#540,.T.);
#542=EDGE_CURVE('E264',#539,#415,#537,.T.);
#543=ORIENTED_EDGE('',*,*,#542,.T.);
#544=EDGE_LOOP('',(#464,#465,#466,#474,#541,#543));
#545=FACE_BOUND('',#544,.T.);
#546=ADVANCED_FACE('F167',(#545),#463,.T.);
#547=CARTESIAN_POINT('',(18.288,-21.0805017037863,0.));
#548=DIRECTION('',(0.,0.866025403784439,0.499999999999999));
#549=DIRECTION('',(0.,-0.499999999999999,0.866025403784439));
#550=AXIS2_PLACEMENT_3D('',#547,#548,#549);
#551=PLANE('',#550);
#552=ORIENTED_EDGE('',*,*,#249,.F.);
#553=DIRECTION('',(-1.,0.,0.));
#554=VECTOR('',#553,1.);
#555=CARTESIAN_POINT('',(18.288,-21.0805017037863,0.));
#556=LINE('',#555,#554);
#557=CARTESIAN_POINT('',(0.756755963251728,-21.0805017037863,0.));
#558=VERTEX_POINT('',#557);
#559=EDGE_CURVE('E315',#223,#558,#556,.T.);
#560=ORIENTED_EDGE('',*,*,#559,.T.);
#561=CARTESIAN_POINT('',(0.756786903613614,-10.5401353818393,-18.25645));
#562=CARTESIAN_POINT('',(0.698141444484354,-10.7590103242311,-17.8773474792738));
#563=CARTESIAN_POINT('',(0.642182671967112,-10.9780647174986,-17.4979341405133));
#564=CARTESIAN_POINT('',(0.536194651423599,-11.4165422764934,-16.7384687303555));
#565=CARTESIAN_POINT('',(0.486165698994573,-11.6359654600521,-16.3584166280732));
#566=CARTESIAN_POINT('',(0.345782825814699,-12.29492733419,-15.2170611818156));
#567=CARTESIAN_POINT('',(0.265175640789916,-12.7350017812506,-14.4548298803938));
#568=CARTESIAN_POINT('',(0.134552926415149,-13.6140160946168,-12.9323324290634));
#569=CARTESIAN_POINT('',(0.0843816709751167,-14.0529500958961,-12.1720764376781));
#570=CARTESIAN_POINT('',(0.0171084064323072,-14.9313815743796,-10.6505884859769));
#571=CARTESIAN_POINT('',(0.,-15.3708789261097,-9.88935674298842));
#572=CARTESIAN_POINT('',(0.,-16.2498736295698,-8.36689325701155));
#573=CARTESIAN_POINT('',(0.0171084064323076,-16.6893709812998,-7.60566151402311));
#574=CARTESIAN_POINT('',(0.0843816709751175,-17.5678024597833,-6.08417356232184));
#575=CARTESIAN_POINT('',(0.13455292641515,-18.0067364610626,-5.32391757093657));
#576=CARTESIAN_POINT('',(0.265175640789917,-18.8857507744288,-3.80142011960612));
#577=CARTESIAN_POINT('',(0.345782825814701,-19.3258252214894,-3.0391888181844));
#578=CARTESIAN_POINT('',(0.486165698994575,-19.9847870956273,-1.89783337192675));
#579=CARTESIAN_POINT('',(0.536194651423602,-20.204210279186,-1.51778126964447));
#580=CARTESIAN_POINT('',(0.642182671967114,-20.6426878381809,-0.75831585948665));
#581=CARTESIAN_POINT('',(0.698141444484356,-20.8617422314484,-0.378902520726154));
#582=CARTESIAN_POINT('',(0.756786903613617,-21.0806171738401,0.000200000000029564));
#583=B_SPLINE_CURVE_WITH_KNOTS('',3,(#561,#562,#563,#564,#565,#566,#567,#568,#569,#570,#571,
#572,#573,#574,#575,#576,#577,#578,#579,#580,#581,#582),.UNSPECIFIED.,.F.,.F.,(4,2,2,2,2,2,2,2,
2,2,4),(0.,1.32496782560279,2.6500016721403,5.30101714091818,7.93835164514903,10.5751758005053,
13.2119999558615,15.8493344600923,18.5003499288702,19.8253837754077,21.1503516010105),.UNSPECIFIED.);
#584=CARTESIAN_POINT('',(0.,-15.8103762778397,-9.12812499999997));
#585=VERTEX_POINT('',#584);
#586=EDGE_CURVE('E252',#585,#558,#583,.T.);
#587=ORIENTED_EDGE('',*,*,#586,.F.);
#588=EDGE_CURVE('E259',#472,#585,#583,.T.);
#589=ORIENTED_EDGE('',*,*,#588,.F.);
#590=ORIENTED_EDGE('',*,*,#473,.F.);
#591=ORIENTED_EDGE('',*,*,#257,.F.);
#592=EDGE_LOOP('',(#552,#560,#587,#589,#590,#591));
#593=FACE_BOUND('',#592,.T.);
#594=ADVANCED_FACE('F242',(#593),#551,.F.);
#595=CARTESIAN_POINT('',(18.288,-10.5402508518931,18.25625));
#596=DIRECTION('',(0.,0.866025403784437,-0.500000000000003));
#597=DIRECTION('',(0.,0.500000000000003,0.866025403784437));
#598=AXIS2_PLACEMENT_3D('',#595,#596,#597);
#599=PLANE('',#598);
#600=ORIENTED_EDGE('',*,*,#216,.F.);
#601=DIRECTION('',(-1.,0.,0.));
#602=VECTOR('',#601,1.);
#603=CARTESIAN_POINT('',(18.288,-10.5402508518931,18.25625));
#604=LINE('',#603,#602);
#605=CARTESIAN_POINT('',(0.756755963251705,-10.5402508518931,18.25625));
#606=VERTEX_POINT('',#605);
#607=EDGE_CURVE('E312',#190,#606,#604,.T.);
#608=ORIENTED_EDGE('',*,*,#607,.T.);
#609=CARTESIAN_POINT('',(0.756786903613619,-21.0806171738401,-0.000199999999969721));
#610=CARTESIAN_POINT('',(0.698141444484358,-20.8617422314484,0.378902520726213));
#611=CARTESIAN_POINT('',(0.642182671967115,-20.6426878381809,0.758315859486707));
#612=CARTESIAN_POINT('',(0.536194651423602,-20.204210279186,1.51778126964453));
#613=CARTESIAN_POINT('',(0.486165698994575,-19.9847870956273,1.8978333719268));
#614=CARTESIAN_POINT('',(0.3457828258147,-19.3258252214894,3.03918881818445));
#615=CARTESIAN_POINT('',(0.265175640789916,-18.8857507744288,3.80142011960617));
#616=CARTESIAN_POINT('',(0.134552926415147,-18.0067364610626,5.32391757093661));
#617=CARTESIAN_POINT('',(0.0843816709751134,-17.5678024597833,6.08417356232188));
#618=CARTESIAN_POINT('',(0.0171084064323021,-16.6893709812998,7.60566151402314));
#619=CARTESIAN_POINT('',(0.,-16.2498736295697,8.36689325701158));
#620=CARTESIAN_POINT('',(0.,-15.3708789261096,9.88935674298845));
#621=CARTESIAN_POINT('',(0.0171084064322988,-14.9313815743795,10.6505884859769));
#622=CARTESIAN_POINT('',(0.0843816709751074,-14.052950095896,12.1720764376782));
#623=CARTESIAN_POINT('',(0.13455292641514,-13.6140160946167,12.9323324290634));
#624=CARTESIAN_POINT('',(0.265175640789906,-12.7350017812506,14.4548298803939));
#625=CARTESIAN_POINT('',(0.345782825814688,-12.29492733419,15.2170611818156));
#626=CARTESIAN_POINT('',(0.486165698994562,-11.6359654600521,16.3584166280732));
#627=CARTESIAN_POINT('',(0.536194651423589,-11.4165422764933,16.7384687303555));
#628=CARTESIAN_POINT('',(0.642182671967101,-10.9780647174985,17.4979341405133));
#629=CARTESIAN_POINT('',(0.698141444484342,-10.759010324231,17.8773474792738));
#630=CARTESIAN_POINT('',(0.756786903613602,-10.5401353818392,18.25645));
#631=B_SPLINE_CURVE_WITH_KNOTS('',3,(#609,#610,#611,#612,#613,#614,#615,#616,#617,#618,#619,
#620,#621,#622,#623,#624,#625,#626,#627,#628,#629,#630),.UNSPECIFIED.,.F.,.F.,(4,2,2,2,2,2,2,2,
2,2,4),(0.,1.32496782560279,2.6500016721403,5.30101714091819,7.93835164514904,10.5751758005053,
13.2119999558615,15.8493344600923,18.5003499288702,19.8253837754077,21.1503516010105),.UNSPECIFIED.);
#632=CARTESIAN_POINT('',(0.,-15.8103762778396,9.12812500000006));
#633=VERTEX_POINT('',#632);
#634=EDGE_CURVE('E190',#633,#606,#631,.T.);
#635=ORIENTED_EDGE('',*,*,#634,.F.);
#636=EDGE_CURVE('E247',#558,#633,#631,.T.);
#637=ORIENTED_EDGE('',*,*,#636,.F.);
#638=ORIENTED_EDGE('',*,*,#559,.F.);
#639=ORIENTED_EDGE('',*,*,#224,.F.);
#640=EDGE_LOOP('',(#600,#608,#635,#637,#638,#639));
#641=FACE_BOUND('',#640,.T.);
#642=ADVANCED_FACE('F238',(#641),#599,.F.);
#643=CARTESIAN_POINT('',(18.288,10.5402508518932,18.25625));
#644=DIRECTION('',(0.,0.,-1.));
#645=DIRECTION('',(0.,1.,0.));
#646=AXIS2_PLACEMENT_3D('',#643,#644,#645);
#647=PLANE('',#646);
#648=ORIENTED_EDGE('',*,*,#398,.F.);
#649=DIRECTION('',(-1.,0.,0.));
#650=VECTOR('',#649,1.);
#651=CARTESIAN_POINT('',(18.288,10.5402508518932,18.25625));
#652=LINE('',#651,#650);
#653=CARTESIAN_POINT('',(0.756755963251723,10.5402508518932,18.25625));
#654=VERTEX_POINT('',#653);
#655=EDGE_CURVE('E309',#395,#654,#652,.T.);
#656=ORIENTED_EDGE('',*,*,#655,.T.);
#657=CARTESIAN_POINT('',(4.0542192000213,-27.9533161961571,18.25625));
#658=CARTESIAN_POINT('',(3.96122717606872,-27.5387982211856,18.25625));
#659=CARTESIAN_POINT('',(3.86882021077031,-27.1241490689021,18.25625));
#660=CARTESIAN_POINT('',(3.68530495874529,-26.2945620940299,18.25625));
#661=CARTESIAN_POINT('',(3.59419667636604,-25.8796242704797,18.25625));
#662=CARTESIAN_POINT('',(3.32300641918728,-24.6343093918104,18.25625));
#663=CARTESIAN_POINT('',(3.14506646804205,-23.8034639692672,18.25625));
#664=CARTESIAN_POINT('',(2.79601214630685,-22.1394972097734,18.25625));
#665=CARTESIAN_POINT('',(2.62490455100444,-21.3063744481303,18.25625));
#666=CARTESIAN_POINT('',(2.29133629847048,-19.6384001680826,18.25625));
#667=CARTESIAN_POINT('',(2.12887556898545,-18.8035486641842,18.25625));
#668=CARTESIAN_POINT('',(1.81591904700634,-17.1384765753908,18.25625));
#669=CARTESIAN_POINT('',(1.66533829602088,-16.3082720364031,18.25625));
#670=CARTESIAN_POINT('',(1.37724193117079,-14.6455811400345,18.25625));
#671=CARTESIAN_POINT('',(1.23972636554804,-13.81309477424,18.25625));
#672=CARTESIAN_POINT('',(0.980848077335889,-12.1457018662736,18.25625));
#673=CARTESIAN_POINT('',(0.859483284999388,-11.3107956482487,18.25625));
#674=CARTESIAN_POINT('',(0.636468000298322,-9.63832410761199,18.25625));
#675=CARTESIAN_POINT('',(0.534817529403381,-8.8007587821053,18.25625));
#676=CARTESIAN_POINT('',(0.354093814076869,-7.11348971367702,18.25625));
#677=CARTESIAN_POINT('',(0.275291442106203,-6.26375652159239,18.25625));
#678=CARTESIAN_POINT('',(0.1456908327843,-4.56213870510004,18.25625));
#679=CARTESIAN_POINT('',(0.0948919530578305,-3.71025413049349,18.25625));
#680=CARTESIAN_POINT('',(0.0242602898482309,-2.00557150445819,18.25625));
#681=CARTESIAN_POINT('',(0.00441316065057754,-1.1527740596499,18.25625));
#682=CARTESIAN_POINT('',(-0.00309314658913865,0.552964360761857,18.25625));
#683=CARTESIAN_POINT('',(0.00924763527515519,1.40590533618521,18.25625));
#684=CARTESIAN_POINT('',(0.0654239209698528,3.11384444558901,18.25625));
#685=CARTESIAN_POINT('',(0.109374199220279,3.96883872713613,18.25625));
#686=CARTESIAN_POINT('',(0.226254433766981,5.67682590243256,18.25625));
#687=CARTESIAN_POINT('',(0.299185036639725,6.52981875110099,18.25625));
#688=CARTESIAN_POINT('',(0.470324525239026,8.23379443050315,18.25625));
#689=CARTESIAN_POINT('',(0.568550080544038,9.08477556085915,18.25625));
#690=CARTESIAN_POINT('',(0.786170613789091,10.7839963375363,18.25625));
#691=CARTESIAN_POINT('',(0.905565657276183,11.6322359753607,18.25625));
#692=CARTESIAN_POINT('',(1.15414497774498,13.2761953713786,18.25625));
#693=CARTESIAN_POINT('',(1.2823387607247,14.0720664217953,18.25625));
#694=CARTESIAN_POINT('',(1.55129899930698,15.6616917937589,18.25625));
#695=CARTESIAN_POINT('',(1.69206580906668,16.4554460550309,18.25625));
#696=CARTESIAN_POINT('',(1.98385895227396,18.0411423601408,18.25625));
#697=CARTESIAN_POINT('',(2.13488635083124,18.8330842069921,18.25625));
#698=CARTESIAN_POINT('',(2.44529392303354,20.4153155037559,18.25625));
#699=CARTESIAN_POINT('',(2.60467401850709,21.2056049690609,18.25625));
#700=CARTESIAN_POINT('',(2.9303090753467,22.7849686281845,18.25625));
#701=CARTESIAN_POINT('',(3.09656574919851,23.5740424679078,18.25625));
#702=CARTESIAN_POINT('',(3.43470265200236,25.1509829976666,18.25625));
#703=CARTESIAN_POINT('',(3.60658289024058,25.9388496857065,18.25625));
#704=CARTESIAN_POINT('',(3.95498431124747,27.5135001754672,18.25625));
#705=CARTESIAN_POINT('',(4.1315051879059,28.300284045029,18.25625));
#706=CARTESIAN_POINT('',(4.48842913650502,29.8729715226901,18.25625));
#707=CARTESIAN_POINT('',(4.66883221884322,30.6588751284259,18.25625));
#708=CARTESIAN_POINT('',(5.2112965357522,32.9999178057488,18.25625));
#709=CARTESIAN_POINT('',(5.57808688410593,34.5539609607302,18.25625));
#710=CARTESIAN_POINT('',(6.32079407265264,37.6598865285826,18.25625));
#711=CARTESIAN_POINT('',(6.69671108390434,39.2117689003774,18.25625));
#712=CARTESIAN_POINT('',(7.45483425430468,42.3119213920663,18.25625));
#713=CARTESIAN_POINT('',(7.83703188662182,43.8601935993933,18.25625));
#714=CARTESIAN_POINT('',(8.41416242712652,46.1816197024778,18.25625));
#715=CARTESIAN_POINT('',(8.60717510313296,46.955252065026,18.25625));
#716=CARTESIAN_POINT('',(8.9943326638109,48.5022325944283,18.25625));
#717=CARTESIAN_POINT('',(9.18847754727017,49.275580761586,18.25625));
#718=CARTESIAN_POINT('',(9.38311482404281,50.0488050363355,18.25625));
#719=B_SPLINE_CURVE_WITH_KNOTS('',3,(#657,#658,#659,#660,#661,#662,#663,#664,#665,#666,#667,
#668,#669,#670,#671,#672,#673,#674,#675,#676,#677,#678,#679,#680,#681,#682,#683,#684,#685,#686,
#687,#688,#689,#690,#691,#692,#693,#694,#695,#696,#697,#698,#699,#700,#701,#702,#703,#704,#705,
#706,#707,#708,#709,#710,#711,#712,#713,#714,#715,#716,#717,#718),.UNSPECIFIED.,.F.,.F.,(4,2,2,
2,2,2,2,2,2,2,2,2,2,2,2,2,2,2,2,2,2,2,2,2,2,2,2,2,2,2,4),(0.,1.27446145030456,2.54892716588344,
5.09796019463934,7.64946118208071,10.2009408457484,12.7321076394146,15.2632837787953,
17.7941352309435,20.3249894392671,22.8847240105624,25.4443998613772,28.0028889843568,
30.5613749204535,33.1291979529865,35.6970782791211,38.2666552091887,40.836240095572,
43.2545085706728,45.6728451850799,48.091433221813,50.5099986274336,52.929170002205,
55.3483453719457,57.7673615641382,60.1863842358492,64.9765661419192,69.7668378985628,
74.551070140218,76.943108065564,79.335143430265),.UNSPECIFIED.);
#720=CARTESIAN_POINT('',(0.,0.,18.25625));
#721=VERTEX_POINT('',#720);
#722=EDGE_CURVE('E191',#721,#654,#719,.T.);
#723=ORIENTED_EDGE('',*,*,#722,.F.);
#724=EDGE_CURVE('E389',#606,#721,#719,.T.);
#725=ORIENTED_EDGE('',*,*,#724,.F.);
#726=ORIENTED_EDGE('',*,*,#607,.F.);
#727=ORIENTED_EDGE('',*,*,#191,.F.);
#728=EDGE_LOOP('',(#648,#656,#723,#725,#726,#727));
#729=FACE_BOUND('',#728,.T.);
#730=ADVANCED_FACE('F241',(#729),#647,.F.);
#731=CARTESIAN_POINT('',(18.288,21.0805017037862,0.));
#732=DIRECTION('',(0.,-0.866025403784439,-0.499999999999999));
#733=DIRECTION('',(0.,0.499999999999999,-0.86602540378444));
#734=AXIS2_PLACEMENT_3D('',#731,#732,#733);
#735=PLANE('',#734);
#736=ORIENTED_EDGE('',*,*,#386,.F.);
#737=ORIENTED_EDGE('',*,*,#453,.T.);
#738=CARTESIAN_POINT('',(0.756786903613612,10.5401353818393,18.25645));
#739=CARTESIAN_POINT('',(0.698141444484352,10.759010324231,17.8773474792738));
#740=CARTESIAN_POINT('',(0.64218267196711,10.9780647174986,17.4979341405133));
#741=CARTESIAN_POINT('',(0.536194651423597,11.4165422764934,16.7384687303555));
#742=CARTESIAN_POINT('',(0.48616569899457,11.6359654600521,16.3584166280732));
#743=CARTESIAN_POINT('',(0.345782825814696,12.29492733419,15.2170611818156));
#744=CARTESIAN_POINT('',(0.265175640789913,12.7350017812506,14.4548298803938));
#745=CARTESIAN_POINT('',(0.134552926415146,13.6140160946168,12.9323324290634));
#746=CARTESIAN_POINT('',(0.0843816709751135,14.0529500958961,12.1720764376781));
#747=CARTESIAN_POINT('',(0.0171084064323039,14.9313815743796,10.6505884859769));
#748=CARTESIAN_POINT('',(0.,15.3708789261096,9.88935674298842));
#749=CARTESIAN_POINT('',(0.,16.2498736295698,8.36689325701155));
#750=CARTESIAN_POINT('',(0.0171084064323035,16.6893709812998,7.60566151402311));
#751=CARTESIAN_POINT('',(0.0843816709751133,17.5678024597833,6.08417356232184));
#752=CARTESIAN_POINT('',(0.134552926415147,18.0067364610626,5.32391757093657));
#753=CARTESIAN_POINT('',(0.265175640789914,18.8857507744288,3.80142011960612));
#754=CARTESIAN_POINT('',(0.345782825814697,19.3258252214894,3.0391888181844));
#755=CARTESIAN_POINT('',(0.486165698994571,19.9847870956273,1.89783337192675));
#756=CARTESIAN_POINT('',(0.536194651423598,20.204210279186,1.51778126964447));
#757=CARTESIAN_POINT('',(0.64218267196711,20.6426878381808,0.758315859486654));
#758=CARTESIAN_POINT('',(0.698141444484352,20.8617422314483,0.378902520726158));
#759=CARTESIAN_POINT('',(0.756786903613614,21.0806171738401,-0.000200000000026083));
#760=B_SPLINE_CURVE_WITH_KNOTS('',3,(#738,#739,#740,#741,#742,#743,#744,#745,#746,#747,#748,
#749,#750,#751,#752,#753,#754,#755,#756,#757,#758,#759),.UNSPECIFIED.,.F.,.F.,(4,2,2,2,2,2,2,2,
2,2,4),(0.,1.32496782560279,2.6500016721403,5.30101714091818,7.93835164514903,10.5751758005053,
13.2119999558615,15.8493344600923,18.5003499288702,19.8253837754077,21.1503516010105),.UNSPECIFIED.);
#761=CARTESIAN_POINT('',(0.,15.8103762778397,9.12812499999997));
#762=VERTEX_POINT('',#761);
#763=EDGE_CURVE('E253',#762,#446,#760,.T.);
#764=ORIENTED_EDGE('',*,*,#763,.F.);
#765=EDGE_CURVE('E258',#654,#762,#760,.T.);
#766=ORIENTED_EDGE('',*,*,#765,.F.);
#767=ORIENTED_EDGE('',*,*,#655,.F.);
#768=ORIENTED_EDGE('',*,*,#396,.F.);
#769=EDGE_LOOP('',(#736,#737,#764,#766,#767,#768));
#770=FACE_BOUND('',#769,.T.);
#771=ADVANCED_FACE('F34',(#770),#735,.F.);
#772=CARTESIAN_POINT('',(0.,0.,0.));
#773=DIRECTION('',(1.,0.,0.));
#774=DIRECTION('',(0.,0.,-1.));
#775=AXIS2_PLACEMENT_3D('',#772,#773,#774);
#776=CONICAL_SURFACE('',#775,18.25625,1.30899693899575);
#777=ORIENTED_EDGE('',*,*,#634,.T.);
#778=ORIENTED_EDGE('',*,*,#724,.T.);
#779=CARTESIAN_POINT('',(0.,0.,0.));
#780=DIRECTION('',(-1.,0.,0.));
#781=DIRECTION('',(0.,0.,1.));
#782=AXIS2_PLACEMENT_3D('',#779,#780,#781);
#783=CIRCLE('',#782,18.25625);
#784=EDGE_CURVE('E304',#633,#721,#783,.T.);
#785=ORIENTED_EDGE('',*,*,#784,.F.);
#786=EDGE_LOOP('',(#777,#778,#785));
#787=FACE_BOUND('',#786,.T.);
#788=ADVANCED_FACE('F388',(#787),#776,.T.);
#789=ORIENTED_EDGE('',*,*,#636,.T.);
#790=EDGE_CURVE('E307',#585,#633,#783,.T.);
#791=ORIENTED_EDGE('',*,*,#790,.F.);
#792=ORIENTED_EDGE('',*,*,#586,.T.);
#793=EDGE_LOOP('',(#789,#791,#792));
#794=FACE_BOUND('',#793,.T.);
#795=ADVANCED_FACE('F390',(#794),#776,.T.);
#796=ORIENTED_EDGE('',*,*,#588,.T.);
#797=EDGE_CURVE('E374',#539,#585,#783,.T.);
#798=ORIENTED_EDGE('',*,*,#797,.F.);
#799=ORIENTED_EDGE('',*,*,#540,.F.);
#800=EDGE_LOOP('',(#796,#798,#799));
#801=FACE_BOUND('',#800,.T.);
#802=ADVANCED_FACE('F371',(#801),#776,.T.);
#803=EDGE_CURVE('E383',#442,#539,#783,.T.);
#804=ORIENTED_EDGE('',*,*,#803,.F.);
#805=ORIENTED_EDGE('',*,*,#443,.T.);
#806=ORIENTED_EDGE('',*,*,#542,.F.);
#807=EDGE_LOOP('',(#804,#805,#806));
#808=FACE_BOUND('',#807,.T.);
#809=ADVANCED_FACE('F208',(#808),#776,.T.);
#810=ORIENTED_EDGE('',*,*,#763,.T.);
#811=ORIENTED_EDGE('',*,*,#447,.T.);
#812=EDGE_CURVE('E303',#762,#442,#783,.T.);
#813=ORIENTED_EDGE('',*,*,#812,.F.);
#814=EDGE_LOOP('',(#810,#811,#813));
#815=FACE_BOUND('',#814,.T.);
#816=ADVANCED_FACE('F381',(#815),#776,.T.);
#817=ORIENTED_EDGE('',*,*,#722,.T.);
#818=ORIENTED_EDGE('',*,*,#765,.T.);
#819=CARTESIAN_POINT('',(0.,0.,0.));
#820=DIRECTION('',(-1.,0.,0.));
#821=DIRECTION('',(0.,0.,1.));
#822=AXIS2_PLACEMENT_3D('',#819,#820,#821);
#823=CIRCLE('',#822,18.25625);
#824=EDGE_CURVE('E282',#721,#762,#823,.T.);
#825=ORIENTED_EDGE('',*,*,#824,.F.);
#826=EDGE_LOOP('',(#817,#818,#825));
#827=FACE_BOUND('',#826,.T.);
#828=ADVANCED_FACE('F161',(#827),#776,.T.);
#829=CARTESIAN_POINT('',(0.,21.0805017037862,0.));
#830=DIRECTION('',(-1.,0.,0.));
#831=DIRECTION('',(0.,0.,1.));
#832=AXIS2_PLACEMENT_3D('',#829,#830,#831);
#833=PLANE('',#832);
#834=CARTESIAN_POINT('',(0.,0.,0.));
#835=DIRECTION('',(-1.,0.,0.));
#836=DIRECTION('',(0.,0.,1.));
#837=AXIS2_PLACEMENT_3D('',#834,#835,#836);
#838=CIRCLE('',#837,12.7);
#839=CARTESIAN_POINT('',(0.,0.,12.7));
#840=VERTEX_POINT('',#839);
#841=EDGE_CURVE('E37',#840,#840,#838,.T.);
#842=ORIENTED_EDGE('',*,*,#841,.F.);
#843=EDGE_LOOP('',(#842));
#844=FACE_BOUND('',#843,.T.);
#845=ORIENTED_EDGE('',*,*,#784,.T.);
#846=ORIENTED_EDGE('',*,*,#824,.T.);
#847=ORIENTED_EDGE('',*,*,#812,.T.);
#848=ORIENTED_EDGE('',*,*,#803,.T.);
#849=ORIENTED_EDGE('',*,*,#797,.T.);
#850=ORIENTED_EDGE('',*,*,#790,.T.);
#851=EDGE_LOOP('',(#845,#846,#847,#848,#849,#850));
#852=FACE_BOUND('',#851,.T.);
#853=ADVANCED_FACE('F158',(#844,#852),#833,.T.);
#854=CARTESIAN_POINT('',(1.2481374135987,0.,0.));
#855=DIRECTION('',(-1.,0.,0.));
#856=DIRECTION('',(0.,0.,1.));
#857=AXIS2_PLACEMENT_3D('',#854,#855,#856);
#858=CONICAL_SURFACE('',#857,10.95375,0.959931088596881);
#859=CARTESIAN_POINT('',(1.13697946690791,0.,0.));
#860=DIRECTION('',(-1.,0.,0.));
#861=DIRECTION('',(0.,0.,1.));
#862=AXIS2_PLACEMENT_3D('',#859,#860,#861);
#863=CIRCLE('',#862,11.1125);
#864=CARTESIAN_POINT('',(1.13697946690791,0.,11.1125));
#865=VERTEX_POINT('',#864);
#866=EDGE_CURVE('E293',#865,#865,#863,.F.);
#867=ORIENTED_EDGE('',*,*,#866,.T.);
#868=EDGE_LOOP('',(#867));
#869=FACE_BOUND('',#868,.T.);
#870=CARTESIAN_POINT('',(0.0253999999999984,0.,0.));
#871=DIRECTION('',(1.,0.,0.));
#872=DIRECTION('',(0.,0.,-1.));
#873=AXIS2_PLACEMENT_3D('',#870,#871,#872);
#874=CIRCLE('',#873,12.7);
#875=CARTESIAN_POINT('',(0.0253999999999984,0.,-12.7));
#876=VERTEX_POINT('',#875);
#877=EDGE_CURVE('E291',#876,#876,#874,.T.);
#878=ORIENTED_EDGE('',*,*,#877,.F.);
#879=EDGE_LOOP('',(#878));
#880=FACE_BOUND('',#879,.T.);
#881=ADVANCED_FACE('F139',(#869,#880),#858,.F.);
#882=CARTESIAN_POINT('',(0.,0.,0.));
#883=DIRECTION('',(1.,0.,0.));
#884=DIRECTION('',(0.,0.,-1.));
#885=AXIS2_PLACEMENT_3D('',#882,#883,#884);
#886=CYLINDRICAL_SURFACE('',#885,12.7);
#887=ORIENTED_EDGE('',*,*,#841,.T.);
#888=EDGE_LOOP('',(#887));
#889=FACE_BOUND('',#888,.T.);
#890=ORIENTED_EDGE('',*,*,#877,.T.);
#891=EDGE_LOOP('',(#890));
#892=FACE_BOUND('',#891,.T.);
#893=ADVANCED_FACE('F130',(#889,#892),#886,.F.);
#894=CARTESIAN_POINT('',(35.1250636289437,0.,0.));
#895=DIRECTION('',(-1.,0.,0.));
#896=DIRECTION('',(0.,0.,1.));
#897=AXIS2_PLACEMENT_3D('',#894,#895,#896);
#898=CONICAL_SURFACE('',#897,0.,1.02974425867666);
#899=CARTESIAN_POINT('',(28.448,0.,0.));
#900=DIRECTION('',(-1.,0.,0.));
#901=DIRECTION('',(0.,0.,1.));
#902=AXIS2_PLACEMENT_3D('',#899,#900,#901);
#903=CIRCLE('',#902,11.1125);
#904=CARTESIAN_POINT('',(28.448,0.,11.1125));
#905=VERTEX_POINT('',#904);
#906=EDGE_CURVE('E287',#905,#905,#903,.T.);
#907=ORIENTED_EDGE('',*,*,#906,.T.);
#908=EDGE_LOOP('',(#907));
#909=FACE_BOUND('',#908,.T.);
#910=CARTESIAN_POINT('',(35.1250636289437,0.,0.));
#911=VERTEX_POINT('',#910);
#912=VERTEX_LOOP('',#911);
#913=FACE_BOUND('',#912,.T.);
#914=ADVANCED_FACE('F127',(#909,#913),#898,.F.);
#915=CARTESIAN_POINT('',(0.,0.,0.));
#916=DIRECTION('',(-1.,0.,0.));
#917=DIRECTION('',(0.,0.,1.));
#918=AXIS2_PLACEMENT_3D('',#915,#916,#917);
#919=CYLINDRICAL_SURFACE('',#918,11.1125);
#920=ORIENTED_EDGE('',*,*,#866,.F.);
#921=EDGE_LOOP('',(#920));
#922=FACE_BOUND('',#921,.T.);
#923=ORIENTED_EDGE('',*,*,#906,.F.);
#924=EDGE_LOOP('',(#923));
#925=FACE_BOUND('',#924,.T.);
#926=ADVANCED_FACE('F129',(#922,#925),#919,.F.);
#927=CLOSED_SHELL('',(#71,#91,#111,#120,#221,#254,#327,#360,#393,#403,#458,#546,#594,#642,#730,
#771,#788,#795,#802,#809,#816,#828,#853,#881,#893,#914,#926));
#928=MANIFOLD_SOLID_BREP('B2',#927);
#929=ADVANCED_BREP_SHAPE_REPRESENTATION('',(#18,#928),#14);
#930=SHAPE_DEFINITION_REPRESENTATION(#9,#929);
ENDSEC;
END-ISO-10303-21;
